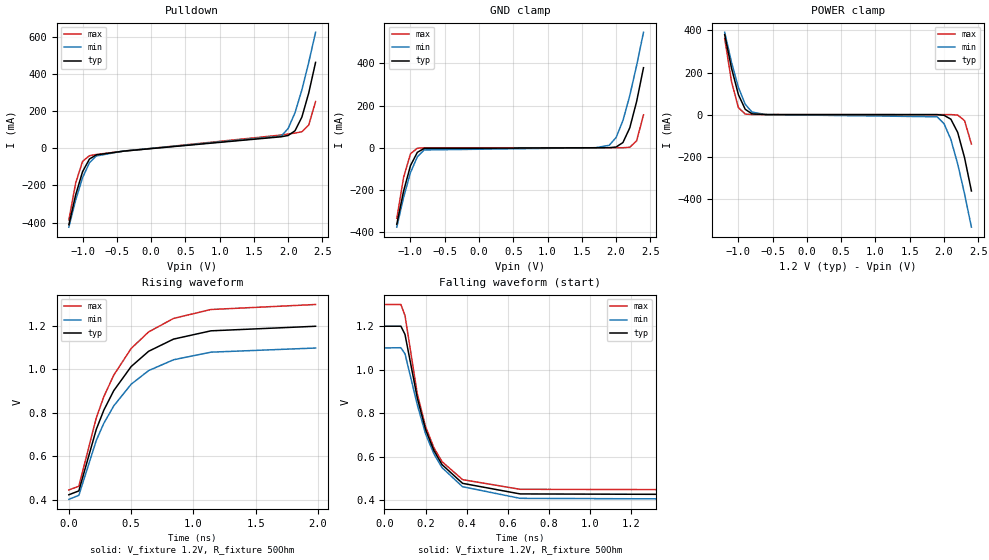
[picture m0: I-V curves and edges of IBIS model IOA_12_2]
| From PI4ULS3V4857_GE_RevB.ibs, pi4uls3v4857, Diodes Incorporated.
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[Model]  IOA_12_2
Model_type  Open_sink
Vmeas=0.8
Vref=1.2
Rref=50
|Variable   typ   min   max
C_comp   4.38p   4.35p   4.41p
|Variable   typ   min   max
[Voltage Range]   1.2   1.1   1.3
[Temperature Range]   40   85   -40
[Pulldown Reference]   0   0   0
[Power Clamp Reference]   1.2   1.1   1.3
[GND Clamp Reference]   0   0   0
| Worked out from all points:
|   slope of the pulldown table from 0 to 0.18 V, typ, clamps not added: 26.9 ohm
|   GND clamp passes 1 mA (typ) near -0.72 V on its own axis
|   POWER clamp passes 1 mA (typ) near -0.72 V on its own axis
|   falling waveform, V_fixture 1.2V, R_fixture 50Ohm: 20-80 % time 143ps typ, 154ps min, 133ps max; typ from 1.2 V to 0.424 V
|   rising waveform, V_fixture 1.2V, R_fixture 50Ohm: 20-80 % time 408ps typ, 410ps min, 406ps max; typ from 0.424 V to 1.2 V
[GND Clamp]
-1.2V     -363mA     -377mA     -335mA
-1.1V     -205mA     -235mA     -140mA
-1V       -84.8mA    -118mA     -28.6mA
-900mV    -21.7mA    -42.8mA    -2.29mA
-800mV    -3.31mA    -10.4mA    -51.5uA
1.7V      183nA      121uA      6.42pA
1.9V      214uA      11.7mA     2.28nA
2V        3.47mA     48.5mA     315nA
2.1V      24.8mA     129mA      39.3uA
2.2V      94.6mA     248mA      2.33mA
2.3V      220mA      391mA      33mA
2.4V      380mA      548mA      156mA
[POWER Clamp]
-1.2V     380mA      391mA      362mA
-1.1V     220mA      248mA      156mA
-1V       94.7mA     129mA      33.1mA
-900mV    24.9mA     48.6mA     2.36mA
-800mV    3.5mA      11.7mA     65.4uA
-600mV    27uA       142uA      19.6uA
1.9V      -320uA     -10.4mA    -62.1uA
2V        -3.38mA    -42.8mA    -65.8uA
2.1V      -21.8mA    -118mA     -120uA
2.2V      -84.9mA    -235mA     -2.36mA
2.3V      -205mA     -377mA     -28.7mA
2.4V      -363mA     -535mA     -140mA
[Pulldown]
| Voltage   I(typ)   I(min)  I(max)
-1.2V     -412mA     -425mA     -386mA
-1.1V     -250mA     -278mA     -186mA
-1V       -126mA     -158mA     -70.7mA
-900mV    -58.2mA    -78mA      -39.8mA
-800mV    -35.5mA    -41.4mA    -33.1mA
-400mV    -15.2mA    -14.6mA    -15.6mA
1.9V      62.2mA     65.8mA     71.5mA
2V        69.2mA     107mA      76.8mA
2.1V      94.5mA     192mA      82mA
2.2V      168mA      315mA      89.2mA
2.3V      298mA      463mA      125mA
2.4V      463mA      625mA      252mA
[Falling Waveform]
V_fixture = 1.2V
V_fixture_min = 1.1V
V_fixture_max = 1.3V
R_fixture = 50Ohm
C_fixture = 0F
|   Time   V(typ)   V(min)   V(max)
0s        1.2V       1.1V       1.3V
80ps      1.2V       1.101V     1.3V
100ps     1.162V     1.073V     1.249V
160ps     869mV      837.4mV    887.5mV
200ps     724.4mV    704.4mV    738.1mV
240ps     628.7mV    613.1mV    641.3mV
280ps     562.8mV    549mV      576.3mV
380ps     476.5mV    460.9mV    493.6mV
660ps     427.8mV    407.4mV    449.1mV
1.98ns    424.2mV    402.9mV    446.3mV
[Rising Waveform]
V_fixture = 1.2V
V_fixture_min = 1.1V
V_fixture_max = 1.3V
R_fixture = 50Ohm
C_fixture = 0F
|   Time   V(typ)   V(min)   V(max)
0s        423.9mV    402.8mV    445.9mV
80ps      441.5mV    421.1mV    463mV
220ps     724.2mV    673.4mV    776.8mV
280ps     811.8mV    751.6mV    873.7mV
360ps     901.9mV    831.9mV    973.1mV
500ps     1.013V     931.8mV    1.096V
640ps     1.083V     994.3mV    1.172V
840ps     1.139V     1.044V     1.234V
1.14ns    1.177V     1.079V     1.275V
1.98ns    1.198V     1.098V     1.298V
[Ramp]
|   typ   min   max
dV/dt_r   0.62/2.47E-10   0.56/2.50E-10   0.68/2.46E-10
dV/dt_f   0.63/1.42E-10   0.56/1.52E-10   0.69/1.34E-10
R_load =   50
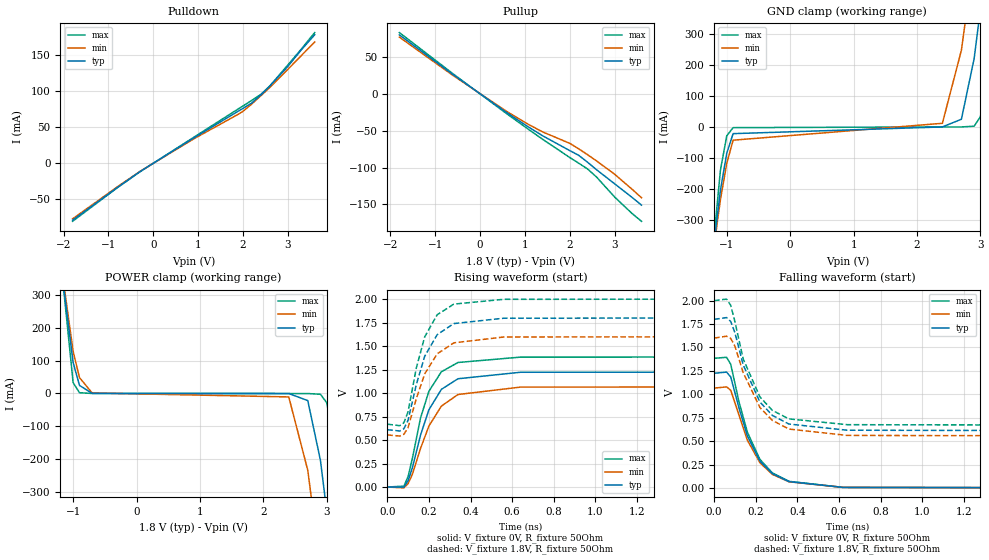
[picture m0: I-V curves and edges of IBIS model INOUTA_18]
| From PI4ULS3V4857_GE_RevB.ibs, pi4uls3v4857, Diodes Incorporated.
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[Model]  INOUTA_18
Model_type  I/O
Vinl = 0.36V
Vinh = 1.44V
Vmeas=0.9
|Variable   typ   min   max
C_comp   4.26p   4.22p   4.30p
|Variable   typ   min   max
[Voltage Range]   1.8   1.6   2.0
[Temperature Range]   40   85   -40
[Pullup Reference]   1.8   1.6   2.0
[Pulldown Reference]   0   0   0
[Power Clamp Reference]   1.8   1.6   2.0
[GND Clamp Reference]   0   0   0
[Driver Schedule]
|Model_Name   Rise_on_dly   Rise_off_dly   Fall_on_dly   Fall_off_dly
IOA_18_1   0.00ns   4.80ns   NA   NA
IOA_18_2   0.00ns   NA   0.00ns   NA
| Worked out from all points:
|   slope of the pulldown table from 0 to 0.27 V, typ, clamps not added: 25.4 ohm
|   slope of the pullup table from 0 to 0.27 V, typ, clamps not added: 23.2 ohm
|   GND clamp passes 1 mA (typ) near -0.72 V on its own axis
|   POWER clamp passes 1 mA (typ) near -0.72 V on its own axis
|   falling waveform, V_fixture 0V, R_fixture 50Ohm: 20-80 % time 129ps typ, 132ps min, 127ps max; typ from 1.22 V to 0.001 V
|   falling waveform, V_fixture 1.8V, R_fixture 50Ohm: 20-80 % time 134ps typ, 139ps min, 129ps max; typ from 1.8 V to 0.611 V
|   rising waveform, V_fixture 0V, R_fixture 50Ohm: 20-80 % time 113ps typ, 125ps min, 102ps max; typ from 0.001 V to 1.22 V
|   rising waveform, V_fixture 1.8V, R_fixture 50Ohm: 20-80 % time 104ps typ, 112ps min, 97.1ps max; typ from 0.611 V to 1.8 V
[GND Clamp]
-1.8V     -1.56A     -1.42A     -1.93A
-1.3V     -542mA     -535mA     -571mA
-1.1V     -205mA     -235mA     -140mA
-1V       -84.8mA    -118mA     -28.6mA
-900mV    -21.7mA    -42.8mA    -2.29mA
2.4V      6.93uA     11.7mA     8.52pA
2.7V      24.8mA     248mA      315nA
2.9V      220mA      548mA      2.33mA
3V        380mA      713mA      33mA
3.1V      561mA      885mA      156mA
3.3V      951mA      1.24A      608mA
3.6V      1.57A      1.79A      1.43A
[POWER Clamp]
-1.8V     1.57A      1.42A      2.01A
-1.3V     561mA      548mA      608mA
-1V       94.7mA     129mA      33.1mA
-900mV    24.9mA     48.6mA     2.36mA
-700mV    238uA      1.67mA     23.2uA
2.4V      -89.8uA    -10.5mA    -78.4uA
2.7V      -21.8mA    -235mA     -88.7uA
2.9V      -205mA     -535mA     -2.39mA
3V        -363mA     -702mA     -28.7mA
3.1V      -542mA     -876mA     -140mA
3.3V      -932mA     -1.24A     -571mA
3.6V      -1.56A     -1.8A      -1.37A
[Pulldown]
| Voltage   I(typ)   I(min)  I(max)
-1.8V     -79mA      -77.1mA    -80.5mA
-800mV    -33.6mA    -32.7mA    -33.9mA
-300mV    -11.8mA    -11.5mA    -12mA
900mV     34.9mA     33.6mA     35.8mA
1.9V      72.3mA     68mA       75.4mA
2V        75.9mA     71.9mA     79.3mA
2.2V      83.6mA     82.2mA     87.2mA
2.4V      94.7mA     93.5mA     95.3mA
2.6V      107mA      105mA      107mA
3V        134mA      130mA      136mA
3.3V      157mA      149mA      158mA
3.6V      178mA      168mA      181mA
[Pullup]   |Note: Vtable = Vcc - Voutput
| Voltage   I(typ)   I(min)  I(max)
-1.8V     80.4mA     77.4mA     83.6mA
-600mV    26.3mA     25.1mA     27.4mA
600mV     -25.5mA    -23.9mA    -27mA
1.1V      -45.6mA    -42mA      -48.9mA
1.4V      -56.9mA    -51.6mA    -61.7mA
2V        -76.9mA    -67mA      -86.3mA
2.2V      -83.3mA    -74.5mA    -94mA
2.4V      -92.9mA    -82.6mA    -102mA
2.6V      -103mA     -91mA      -113mA
3V        -122mA     -109mA     -140mA
3.4V      -141mA     -130mA     -163mA
3.6V      -151mA     -141mA     -173mA
[Falling Waveform]
V_fixture = 0V
V_fixture_min = 0V
V_fixture_max = 0V
R_fixture = 50Ohm
C_fixture = 0F
|   Time   V(typ)   V(min)   V(max)
0s        1.224V     1.066V     1.384V
60ps      1.237V     1.079V     1.395V
80ps      1.185V     1.043V     1.32V
120ps     852.5mV    775.8mV    917mV
160ps     555.2mV    509.5mV    595.4mV
220ps     288.2mV    270mV      306mV
280ps     152.2mV    144.8mV    160.9mV
360ps     67.7mV     65.7mV     70.54mV
620ps     5.789mV    5.873mV    5.809mV
1.98ns    1.014mV    924.2uV    1.09mV
[Falling Waveform]
V_fixture = 1.8V
V_fixture_min = 1.6V
V_fixture_max = 2.0V
R_fixture = 50Ohm
C_fixture = 0F
|   Time   V(typ)   V(min)   V(max)
0s        1.8V       1.6V       2V
60ps      1.819V     1.62V      2.016V
80ps      1.777V     1.596V     1.95V
100ps     1.659V     1.515V     1.777V
140ps     1.313V     1.231V     1.377V
220ps     918.4mV    859.7mV    972.9mV
280ps     774.7mV    720.8mV    828.3mV
360ps     682.2mV    628.6mV    737.2mV
640ps     616.3mV    560.8mV    675.5mV
1.98ns    611mV      555.4mV    669.9mV
[Rising Waveform]
V_fixture = 0V
V_fixture_min = 0V
V_fixture_max = 0V
R_fixture = 50Ohm
C_fixture = 0F
|   Time   V(typ)   V(min)   V(max)
0s        1.014mV    924.1uV    1.09mV
80ps      -483.6uV   -7.821mV   10.41mV
100ps     67.65mV    36.61mV    111.6mV
120ps     201.2mV    132.3mV    299.9mV
160ps     555.1mV    412.4mV    735.9mV
200ps     822.2mV    649.5mV    1.019V
260ps     1.04V      862mV      1.227V
340ps     1.153V     985.3mV    1.326V
640ps     1.222V     1.064V     1.383V
1.98ns    1.224V     1.066V     1.384V
[Rising Waveform]
V_fixture = 1.8V
V_fixture_min = 1.6V
V_fixture_max = 2.0V
R_fixture = 50Ohm
C_fixture = 0F
|   Time   V(typ)   V(min)   V(max)
0s        611mV      555.4mV    669.9mV
60ps      597mV      543.2mV    653.7mV
80ps      620.9mV    562.3mV    685.2mV
100ps     711.7mV    633.5mV    802.4mV
140ps     1.094V     944.3mV    1.27V
180ps     1.393V     1.205V     1.599V
240ps     1.622V     1.418V     1.834V
320ps     1.74V      1.535V     1.947V
560ps     1.797V     1.597V     1.998V
1.98ns    1.8V       1.6V       2V
[Ramp]
|   typ   min   max
dV/dt_r   0.99/0.74E-10   0.86/0.82E-10   1.12/0.66E-10
dV/dt_f   0.99/1.27E-10   0.87/1.31E-10   1.12/1.26E-10
R_load =   50.0000
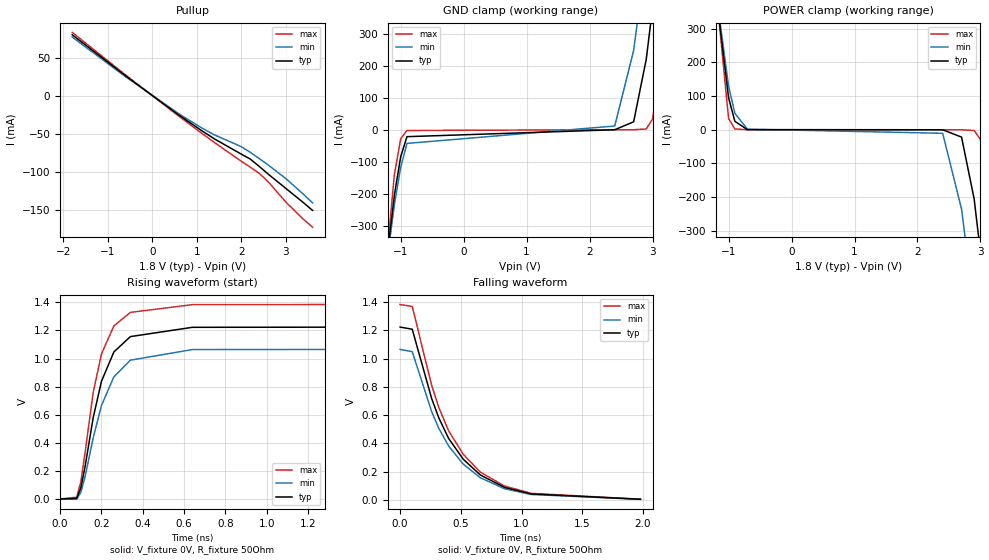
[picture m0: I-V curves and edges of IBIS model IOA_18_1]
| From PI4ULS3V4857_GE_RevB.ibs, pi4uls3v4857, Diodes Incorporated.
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[Model]  IOA_18_1
Model_type  Open_source
Vmeas=0.6
Vref=0
Rref=50
|Variable   typ   min   max
C_comp   4.26p   4.22p   4.30p
|Variable   typ   min   max
[Voltage Range]   1.8   1.6   2.0
[Temperature Range]   40   85   -40
[Pullup Reference]   1.8   1.6   2.0
[Power Clamp Reference]   1.8   1.6   2.0
[GND Clamp Reference]   0   0   0
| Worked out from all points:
|   slope of the pullup table from 0 to 0.27 V, typ, clamps not added: 23.2 ohm
|   GND clamp passes 1 mA (typ) near -0.72 V on its own axis
|   POWER clamp passes 1 mA (typ) near -0.72 V on its own axis
|   falling waveform, V_fixture 0V, R_fixture 50Ohm: 20-80 % time 390ps typ, 395ps min, 387ps max; typ from 1.22 V to 0.005 V
|   rising waveform, V_fixture 0V, R_fixture 50Ohm: 20-80 % time 113ps typ, 125ps min, 102ps max; typ from 0.003 V to 1.22 V
[GND Clamp]
-1.8V     -1.56A     -1.42A     -1.93A
-1.3V     -542mA     -535mA     -571mA
-1.1V     -205mA     -235mA     -140mA
-1V       -84.8mA    -118mA     -28.6mA
-900mV    -21.7mA    -42.8mA    -2.29mA
2.4V      6.93uA     11.7mA     8.52pA
2.7V      24.8mA     248mA      315nA
2.9V      220mA      548mA      2.33mA
3V        380mA      713mA      33mA
3.1V      561mA      885mA      156mA
3.3V      951mA      1.24A      608mA
3.6V      1.57A      1.79A      1.43A
[POWER Clamp]
-1.8V     1.57A      1.42A      2.01A
-1.3V     561mA      548mA      608mA
-1V       94.7mA     129mA      33.1mA
-900mV    24.9mA     48.6mA     2.36mA
-700mV    238uA      1.67mA     23.2uA
2.4V      -89.8uA    -10.5mA    -78.4uA
2.7V      -21.8mA    -235mA     -88.7uA
2.9V      -205mA     -535mA     -2.39mA
3V        -363mA     -702mA     -28.7mA
3.1V      -542mA     -876mA     -140mA
3.3V      -932mA     -1.24A     -571mA
3.6V      -1.56A     -1.8A      -1.37A
[Pullup]   |Note: Vtable = Vcc - Voutput
| Voltage   I(typ)   I(min)  I(max)
-1.8V     80.4mA     77.4mA     83.6mA
-600mV    26.3mA     25.1mA     27.4mA
600mV     -25.5mA    -23.9mA    -27mA
1.1V      -45.6mA    -42mA      -48.9mA
1.4V      -56.9mA    -51.6mA    -61.7mA
2V        -76.9mA    -67mA      -86.3mA
2.2V      -83.3mA    -74.5mA    -94mA
2.4V      -92.9mA    -82.6mA    -102mA
2.6V      -103mA     -91mA      -113mA
3V        -122mA     -109mA     -140mA
3.4V      -141mA     -130mA     -163mA
3.6V      -151mA     -141mA     -173mA
[Falling Waveform]
V_fixture = 0V
V_fixture_min = 0V
V_fixture_max = 0V
R_fixture = 50Ohm
C_fixture = 0F
|   Time   V(typ)   V(min)   V(max)
0s        1.224V     1.066V     1.384V
100ps     1.209V     1.05V      1.37V
260ps     718mV      625.4mV    811.5mV
320ps     578.8mV    505.1mV    652.6mV
400ps     435mV      381.4mV    488.9mV
520ps     288.5mV    253.8mV    323.4mV
660ps     177.5mV    157.5mV    197.8mV
860ps     88.74mV    79.47mV    98.33mV
1.08ns    42.37mV    38.44mV    46.59mV
1.98ns    4.714mV    4.28mV     5.102mV
[Rising Waveform]
V_fixture = 0V
V_fixture_min = 0V
V_fixture_max = 0V
R_fixture = 50Ohm
C_fixture = 0F
|   Time   V(typ)   V(min)   V(max)
0s        3.004mV    2.684mV    3.261mV
80ps      7.001mV    493.1uV    15.39mV
100ps     81.21mV    50.42mV    123.4mV
120ps     227.2mV    156.6mV    325.4mV
160ps     581.3mV    438.1mV    759.7mV
200ps     838.8mV    666.9mV    1.033V
260ps     1.047V     870.6mV    1.232V
340ps     1.156V     988.7mV    1.328V
640ps     1.222V     1.064V     1.383V
1.98ns    1.224V     1.066V     1.384V
[Ramp]
|   typ   min   max
dV/dt_r   0.99/0.74E-10   0.86/0.82E-10   1.12/0.65E-10
dV/dt_f   0.98/3.91E-10   0.86/3.96E-10   1.11/3.87E-10
R_load =   50.0000
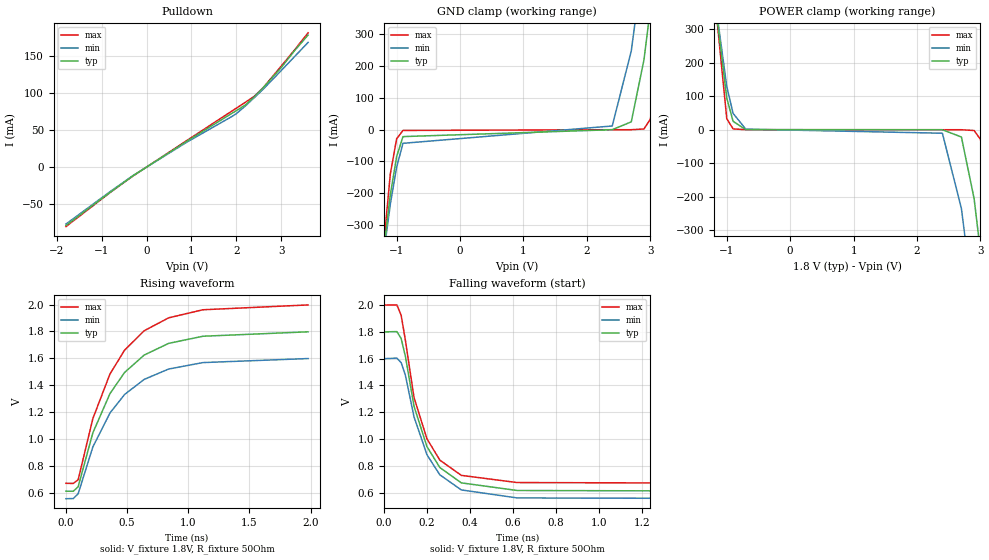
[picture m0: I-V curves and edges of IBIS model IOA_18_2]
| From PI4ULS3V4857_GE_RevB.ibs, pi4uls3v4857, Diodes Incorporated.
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[Model]  IOA_18_2
Model_type  Open_sink
Vmeas=1.0
Vref=1.8
Rref=50
|Variable   typ   min   max
C_comp   4.26p   4.22p   4.30p
|Variable   typ   min   max
[Voltage Range]   1.8   1.6   2.0
[Temperature Range]   40   85   -40
[Pullup Reference]   1.8   1.6   2.0
[Pulldown Reference]   0   0   0
[Power Clamp Reference]   1.8   1.6   2.0
[GND Clamp Reference]   0   0   0
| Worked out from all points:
|   slope of the pulldown table from 0 to 0.27 V, typ, clamps not added: 25.4 ohm
|   GND clamp passes 1 mA (typ) near -0.72 V on its own axis
|   POWER clamp passes 1 mA (typ) near -0.72 V on its own axis
|   falling waveform, V_fixture 1.8V, R_fixture 50Ohm: 20-80 % time 127ps typ, 134ps min, 121ps max; typ from 1.8 V to 0.611 V
|   rising waveform, V_fixture 1.8V, R_fixture 50Ohm: 20-80 % time 392ps typ, 398ps min, 389ps max; typ from 0.611 V to 1.8 V
[GND Clamp]
-1.8V     -1.56A     -1.42A     -1.93A
-1.3V     -542mA     -535mA     -571mA
-1.1V     -205mA     -235mA     -140mA
-1V       -84.8mA    -118mA     -28.6mA
-900mV    -21.7mA    -42.8mA    -2.29mA
2.4V      6.93uA     11.7mA     8.52pA
2.7V      24.8mA     248mA      315nA
2.9V      220mA      548mA      2.33mA
3V        380mA      713mA      33mA
3.1V      561mA      885mA      156mA
3.3V      951mA      1.24A      608mA
3.6V      1.57A      1.79A      1.43A
[POWER Clamp]
-1.8V     1.57A      1.42A      2.01A
-1.3V     561mA      548mA      608mA
-1V       94.7mA     129mA      33.1mA
-900mV    24.9mA     48.6mA     2.36mA
-700mV    238uA      1.67mA     23.2uA
2.4V      -89.8uA    -10.5mA    -78.4uA
2.7V      -21.8mA    -235mA     -88.7uA
2.9V      -205mA     -535mA     -2.39mA
3V        -363mA     -702mA     -28.7mA
3.1V      -542mA     -876mA     -140mA
3.3V      -932mA     -1.24A     -571mA
3.6V      -1.56A     -1.8A      -1.37A
[Pulldown]
| Voltage   I(typ)   I(min)  I(max)
-1.8V     -79mA      -77.1mA    -80.5mA
-800mV    -33.6mA    -32.7mA    -33.9mA
-300mV    -11.8mA    -11.5mA    -12mA
900mV     34.9mA     33.6mA     35.8mA
1.9V      72.3mA     68mA       75.4mA
2V        75.9mA     71.9mA     79.3mA
2.2V      83.6mA     82.2mA     87.2mA
2.4V      94.7mA     93.5mA     95.3mA
2.6V      107mA      105mA      107mA
3V        134mA      130mA      136mA
3.3V      157mA      149mA      158mA
3.6V      178mA      168mA      181mA
[Falling Waveform]
V_fixture = 1.8V
V_fixture_min = 1.6V
V_fixture_max = 2.0V
R_fixture = 50Ohm
C_fixture = 0F
|   Time   V(typ)   V(min)   V(max)
0s        1.8V       1.6V       2V
60ps      1.802V     1.604V     2.001V
80ps      1.751V     1.571V     1.925V
100ps     1.616V     1.475V     1.735V
140ps     1.245V     1.166V     1.31V
200ps     944.6mV    883.9mV    1.003V
260ps     788.3mV    733.8mV    843.5mV
360ps     673.6mV    620.9mV    729.5mV
620ps     616.6mV    561.1mV    675.8mV
1.98ns    611mV      555.4mV    669.9mV
[Rising Waveform]
V_fixture = 1.8V
V_fixture_min = 1.6V
V_fixture_max = 2.0V
R_fixture = 50Ohm
C_fixture = 0F
|   Time   V(typ)   V(min)   V(max)
0s        611mV      555.4mV    669.9mV
60ps      610.8mV    556.2mV    668.9mV
100ps     644mV      592.2mV    696.4mV
220ps     1.045V     940mV      1.151V
360ps     1.337V     1.193V     1.483V
480ps     1.495V     1.331V     1.661V
640ps     1.624V     1.443V     1.805V
840ps     1.711V     1.52V      1.901V
1.12ns    1.764V     1.568V     1.961V
1.98ns    1.797V     1.598V     1.997V
[Ramp]
|   typ   min   max
dV/dt_r   0.95/2.38E-10   0.84/2.41E-10   1.06/2.35E-10
dV/dt_f   0.96/1.29E-10   0.84/1.34E-10   1.07/1.24E-10
R_load =   50
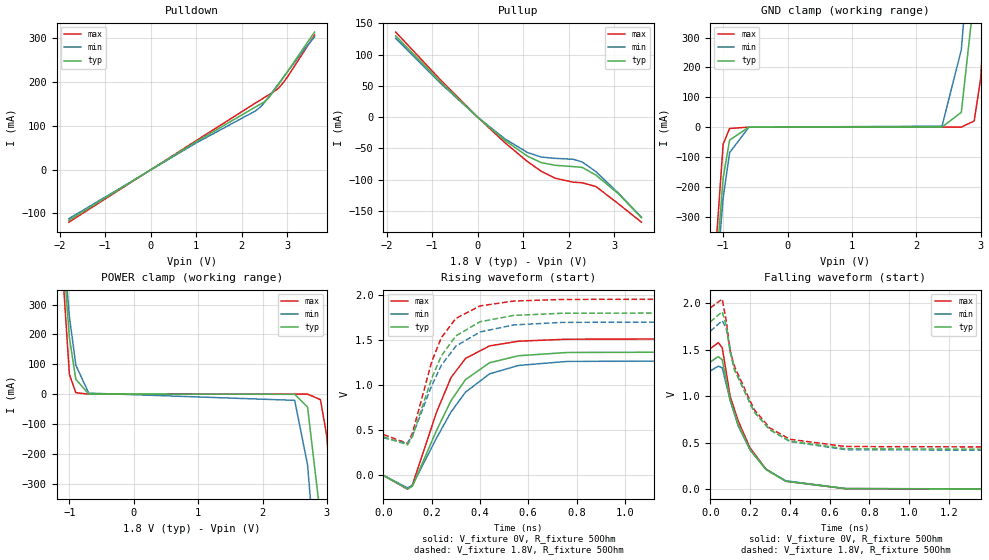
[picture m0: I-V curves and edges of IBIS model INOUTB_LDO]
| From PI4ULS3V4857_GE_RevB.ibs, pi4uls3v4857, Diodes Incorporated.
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[Model]  INOUTB_LDO
Model_type  I/O
Vinl = 0.36V
Vinh = 1.44V
Vmeas=0.9
|Variable   typ   min   max
C_comp   6.81p   6.40p   6.97p
|Variable   typ   min   max
[Voltage Range]   1.8   1.7   1.95
[Temperature Range]   40   85   -40
[Pullup Reference]   1.8   1.7   1.95
[Pulldown Reference]   0   0   0
[Power Clamp Reference]   1.8   1.7   1.95
[GND Clamp Reference]   0   0   0
[Driver Schedule]
|Model_Name   Rise_on_dly   Rise_off_dly   Fall_on_dly   Fall_off_dly
IOB_LDO_1   0.00ns   4.80ns   NA   NA
IOB_LDO_2   0.00ns   NA   0.00ns   NA
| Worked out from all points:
|   slope of the pulldown table from 0 to 0.27 V, typ, clamps not added: 15.5 ohm
|   slope of the pullup table from 0 to 0.27 V, typ, clamps not added: 15.5 ohm
|   GND clamp passes 1 mA (typ) near -0.71 V on its own axis
|   POWER clamp passes 1 mA (typ) near -0.71 V on its own axis
|   falling waveform, V_fixture 0V, R_fixture 50Ohm: 20-80 % time 162ps typ, 166ps min, 160ps max; typ from 1.37 V to 0 V
|   falling waveform, V_fixture 1.8V, R_fixture 50Ohm: 20-80 % time 173ps typ, 177ps min, 167ps max; typ from 1.8 V to 0.426 V
|   rising waveform, V_fixture 0V, R_fixture 50Ohm: 20-80 % time 168ps typ, 188ps min, 139ps max; typ from 0 V to 1.37 V
|   rising waveform, V_fixture 1.8V, R_fixture 50Ohm: 20-80 % time 140ps typ, 152ps min, 121ps max; typ from 0.426 V to 1.8 V
[GND Clamp]
-1.8V     -3.11A     -2.84A     -3.86A
-1.2V     -725mA     -754mA     -669mA
-1V       -170mA     -237mA     -57.3mA
-900mV    -43.4mA    -85.5mA    -4.58mA
-600mV    -19.2uA    -301uA     -6.81nA
2.4V      13.9uA     3.3mA      19.8pA
2.7V      49.7mA     259mA      7.25uA
2.9V      440mA      782mA      20.6mA
3V        761mA      1.1A       162mA
3.1V      1.12A      1.43A      503mA
3.2V      1.5A       1.77A      963mA
3.6V      3.15A      3.21A      3.16A
[POWER Clamp]
-1.8V     3.15A      2.84A      4.03A
-1.2V     761mA      782mA      724mA
-1V       189mA      259mA      66.1mA
-900mV    49.7mA     97.1mA     4.69mA
-700mV    452uA      3.32mA     23.4uA
2.5V      -596uA     -20.8mA    -81.4uA
2.7V      -43.5mA    -237mA     -98.1uA
2.9V      -410mA     -754mA     -18.4mA
3V        -725mA     -1.07A     -142mA
3.1V      -1.08A     -1.4A      -460mA
3.2V      -1.47A     -1.75A     -899mA
3.6V      -3.11A     -3.22A     -3.02A
[Pulldown]
| Voltage   I(typ)   I(min)  I(max)
-1.8V     -116mA     -112mA     -120mA
1V        63.9mA     61mA       66.2mA
2.3V      143mA      134mA      152mA
2.4V      149mA      142mA      158mA
2.5V      155mA      153mA      165mA
2.6V      165mA      167mA      171mA
2.8V      193mA      195mA      185mA
2.9V      208mA      209mA      197mA
3V        223mA      223mA      211mA
3.4V      284mA      278mA      275mA
3.6V      314mA      303mA      307mA
[Pullup]   |Note: Vtable = Vcc - Voutput
| Voltage   I(typ)   I(min)  I(max)
-1.8V     130mA      126mA      136mA
-800mV    55.3mA     53.1mA     58.4mA
0V        15.2pA     41pA       15.6pA
600mV     -37.3mA    -34.8mA    -40.9mA
1.1V      -62.6mA    -56.8mA    -71.3mA
1.4V      -72.8mA    -63.8mA    -86.6mA
1.7V      -77mA      -65.9mA    -97.7mA
2.1V      -79.1mA    -67.4mA    -104mA
2.3V      -80.4mA    -71.7mA    -105mA
2.6V      -92.8mA    -87.2mA    -111mA
3.1V      -123mA     -122mA     -139mA
3.6V      -161mA     -160mA     -168mA
[Falling Waveform]
V_fixture = 0V
V_fixture_min = 0V
V_fixture_max = 0V
R_fixture = 50Ohm
C_fixture = 0F
|   Time   V(typ)   V(min)   V(max)
0s        1.368V     1.273V     1.512V
40ps      1.427V     1.324V     1.577V
60ps      1.393V     1.307V     1.524V
100ps     957.6mV    955mV      999.2mV
140ps     700.1mV    682.9mV    736.7mV
200ps     425.4mV    421.9mV    443.5mV
280ps     211mV      214.5mV    216.8mV
380ps     84.95mV    90.05mV    85.42mV
680ps     5.872mV    6.478mV    5.434mV
1.98ns    -762.7nV   5.088uV    -2.572uV
[Falling Waveform]
V_fixture = 1.8V
V_fixture_min = 1.7V
V_fixture_max = 1.95V
R_fixture = 50Ohm
C_fixture = 0F
|   Time   V(typ)   V(min)   V(max)
0s        1.8V       1.7V       1.95V
60ps      1.91V      1.813V     2.046V
80ps      1.762V     1.731V     1.815V
100ps     1.477V     1.509V     1.487V
120ps     1.295V     1.295V     1.33V
220ps     836.1mV    833.6mV    859mV
300ps     638.6mV    639.5mV    658.2mV
400ps     517.1mV    513.7mV    537.2mV
680ps     434.6mV    424.7mV    458.8mV
1.98ns    426.2mV    415.1mV    451.4mV
[Rising Waveform]
V_fixture = 0V
V_fixture_min = 0V
V_fixture_max = 0V
R_fixture = 50Ohm
C_fixture = 0F
|   Time   V(typ)   V(min)   V(max)
0s        122.5uV    141.4uV    94.05uV
100ps     -150.9mV   -137.8mV   -152.7mV
120ps     -121.2mV   -110.9mV   -106.7mV
220ps     496.1mV    413.1mV    697.7mV
280ps     825.5mV    700.2mV    1.081V
340ps     1.059V     920.1mV    1.293V
440ps     1.246V     1.123V     1.432V
560ps     1.323V     1.216V     1.484V
760ps     1.359V     1.26V      1.506V
1.98ns    1.368V     1.273V     1.512V
[Rising Waveform]
V_fixture = 1.8V
V_fixture_min = 1.7V
V_fixture_max = 1.95V
R_fixture = 50Ohm
C_fixture = 0F
|   Time   V(typ)   V(min)   V(max)
0s        426.3mV    415.2mV    451.5mV
100ps     337.8mV    352.9mV    353.3mV
120ps     428mV      435.1mV    464.7mV
200ps     1.071V     991.5mV    1.256V
240ps     1.322V     1.217V     1.523V
300ps     1.542V     1.429V     1.736V
400ps     1.699V     1.586V     1.874V
540ps     1.769V     1.664V     1.928V
740ps     1.793V     1.692V     1.946V
1.98ns    1.8V       1.7V       1.95V
[Ramp]
|   typ   min   max
dV/dt_r   1.14/1.65E-10   1.06/1.69E-10   1.27/1.64E-10
dV/dt_f   1.27/1.22E-10   1.13/1.36E-10   1.33/1.00E-10
R_load =   50.0000
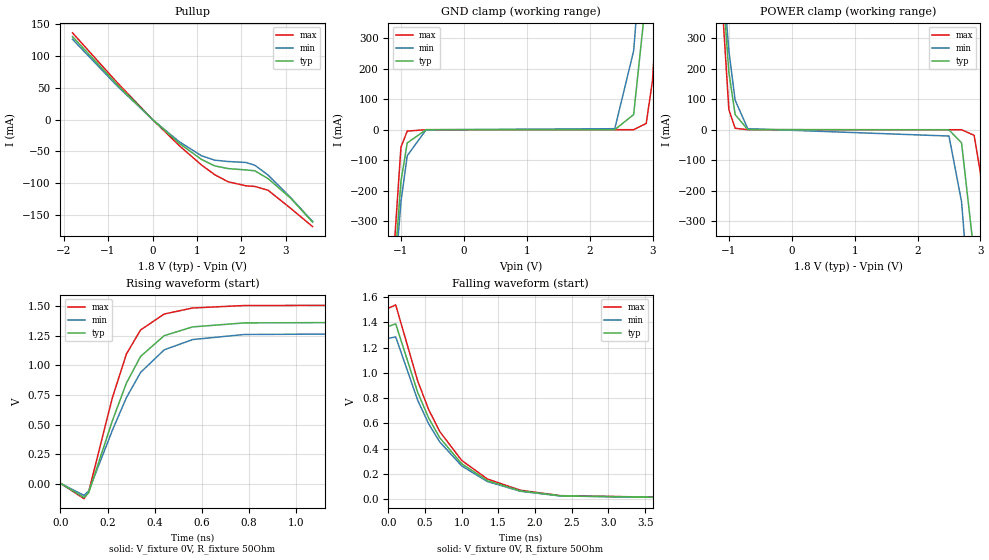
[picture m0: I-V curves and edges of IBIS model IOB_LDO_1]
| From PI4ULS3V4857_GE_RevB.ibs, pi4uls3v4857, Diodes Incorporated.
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[Model]  IOB_LDO_1
Model_type  Open_source
Vmeas=0.6
Vref=0
Rref=50
|Variable   typ   min   max
C_comp   6.81p   6.40p   6.97p
|Variable   typ   min   max
[Voltage Range]   1.8   1.7   1.95
[Temperature Range]   40   85   -40
[Pullup Reference]   1.8   1.7   1.95
[Power Clamp Reference]   1.8   1.7   1.95
[GND Clamp Reference]   0   0   0
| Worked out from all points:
|   slope of the pullup table from 0 to 0.27 V, typ, clamps not added: 15.5 ohm
|   GND clamp passes 1 mA (typ) near -0.71 V on its own axis
|   POWER clamp passes 1 mA (typ) near -0.71 V on its own axis
|   falling waveform, V_fixture 0V, R_fixture 50Ohm: 20-80 % time 749ps typ, 758ps min, 742ps max; typ from 1.37 V to 0.003 V
|   rising waveform, V_fixture 0V, R_fixture 50Ohm: 20-80 % time 168ps typ, 188ps min, 140ps max; typ from 0.003 V to 1.37 V
[GND Clamp]
-1.8V     -3.11A     -2.84A     -3.86A
-1.2V     -725mA     -754mA     -669mA
-1V       -170mA     -237mA     -57.3mA
-900mV    -43.4mA    -85.5mA    -4.58mA
-600mV    -19.2uA    -301uA     -6.81nA
2.4V      13.9uA     3.3mA      19.8pA
2.7V      49.7mA     259mA      7.25uA
2.9V      440mA      782mA      20.6mA
3V        761mA      1.1A       162mA
3.1V      1.12A      1.43A      503mA
3.2V      1.5A       1.77A      963mA
3.6V      3.15A      3.21A      3.16A
[POWER Clamp]
-1.8V     3.15A      2.84A      4.03A
-1.2V     761mA      782mA      724mA
-1V       189mA      259mA      66.1mA
-900mV    49.7mA     97.1mA     4.69mA
-700mV    452uA      3.32mA     23.4uA
2.5V      -596uA     -20.8mA    -81.4uA
2.7V      -43.5mA    -237mA     -98.1uA
2.9V      -410mA     -754mA     -18.4mA
3V        -725mA     -1.07A     -142mA
3.1V      -1.08A     -1.4A      -460mA
3.2V      -1.47A     -1.75A     -899mA
3.6V      -3.11A     -3.22A     -3.02A
[Pullup]   |Note: Vtable = Vcc - Voutput
| Voltage   I(typ)   I(min)  I(max)
-1.8V     130mA      126mA      136mA
-800mV    55.3mA     53.1mA     58.4mA
0V        15.2pA     41pA       15.6pA
600mV     -37.3mA    -34.8mA    -40.9mA
1.1V      -62.6mA    -56.8mA    -71.3mA
1.4V      -72.8mA    -63.8mA    -86.6mA
1.7V      -77mA      -65.9mA    -97.7mA
2.1V      -79.1mA    -67.4mA    -104mA
2.3V      -80.4mA    -71.7mA    -105mA
2.6V      -92.8mA    -87.2mA    -111mA
3.1V      -123mA     -122mA     -139mA
3.6V      -161mA     -160mA     -168mA
[Falling Waveform]
V_fixture = 0V
V_fixture_min = 0V
V_fixture_max = 0V
R_fixture = 50Ohm
C_fixture = 0F
|   Time   V(typ)   V(min)   V(max)
0s        1.368V     1.273V     1.512V
100ps     1.388V     1.285V     1.538V
400ps     845mV      782.5mV    935.2mV
550ps     641.2mV    595.6mV    707.7mV
700ps     486.3mV    452.9mV    535.3mV
1ns       279.3mV    262.5mV    305.8mV
1.35ns    146.2mV    138.7mV    159.2mV
1.8ns     64.77mV    61.77mV    69.9mV
2.35ns    25.37mV    24.49mV    27.15mV
4.95ns    3.267mV    3.134mV    3.42mV
[Rising Waveform]
V_fixture = 0V
V_fixture_min = 0V
V_fixture_max = 0V
R_fixture = 50Ohm
C_fixture = 0F
|   Time   V(typ)   V(min)   V(max)
0s        2.995mV    2.842mV    3.17mV
100ps     -117.2mV   -99.13mV   -127.1mV
120ps     -74.76mV   -61.46mV   -66.85mV
220ps     531.5mV    450.9mV    726.8mV
280ps     852.1mV    728.9mV    1.098V
340ps     1.077V     941.6mV    1.301V
440ps     1.252V     1.132V     1.435V
560ps     1.326V     1.219V     1.486V
780ps     1.36V      1.262V     1.507V
1.98ns    1.368V     1.273V     1.512V
[Ramp]
|   typ   min   max
dV/dt_r   1.19/1.21E-10   1.10/1.34E-10   1.31/1.00E-10
dV/dt_f   1.12/7.46E-10   1.04/7.53E-10   1.24/7.40E-10
R_load =   50.0000
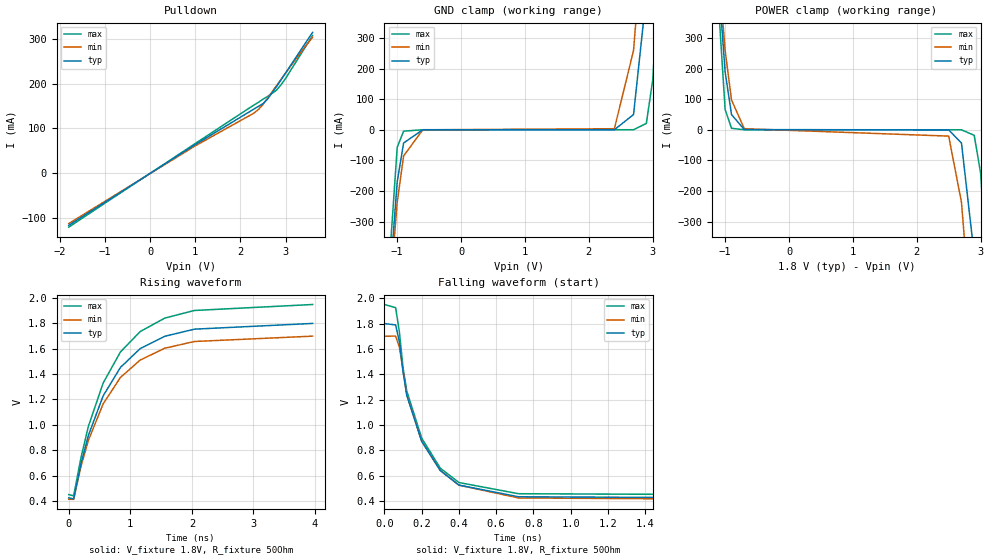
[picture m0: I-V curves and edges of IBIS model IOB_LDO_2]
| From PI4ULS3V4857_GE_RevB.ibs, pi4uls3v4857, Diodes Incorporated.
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[Model]  IOB_LDO_2
Model_type  Open_sink
Vmeas=0.9
Vref=1.2
Rref=50
|Variable   typ   min   max
C_comp   6.81p   6.40p   6.97p
|Variable   typ   min   max
[Voltage Range]   1.8   1.7   1.95
[Temperature Range]   40   85   -40
[Pullup Reference]   1.8   1.7   1.95
[Pulldown Reference]   0   0   0
[Power Clamp Reference]   1.8   1.7   1.95
[GND Clamp Reference]   0   0   0
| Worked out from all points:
|   slope of the pulldown table from 0 to 0.27 V, typ, clamps not added: 15.5 ohm
|   GND clamp passes 1 mA (typ) near -0.71 V on its own axis
|   POWER clamp passes 1 mA (typ) near -0.71 V on its own axis
|   falling waveform, V_fixture 1.8V, R_fixture 50Ohm: 20-80 % time 176ps typ, 185ps min, 167ps max; typ from 1.8 V to 0.426 V
|   rising waveform, V_fixture 1.8V, R_fixture 50Ohm: 20-80 % time 772ps typ, 779ps min, 764ps max; typ from 0.426 V to 1.8 V
[GND Clamp]
-1.8V     -3.11A     -2.84A     -3.86A
-1.2V     -725mA     -754mA     -669mA
-1V       -170mA     -237mA     -57.3mA
-900mV    -43.4mA    -85.5mA    -4.58mA
-600mV    -19.2uA    -301uA     -6.81nA
2.4V      13.9uA     3.3mA      19.8pA
2.7V      49.7mA     259mA      7.25uA
2.9V      440mA      782mA      20.6mA
3V        761mA      1.1A       162mA
3.1V      1.12A      1.43A      503mA
3.2V      1.5A       1.77A      963mA
3.6V      3.15A      3.21A      3.16A
[POWER Clamp]
-1.8V     3.15A      2.84A      4.03A
-1.2V     761mA      782mA      724mA
-1V       189mA      259mA      66.1mA
-900mV    49.7mA     97.1mA     4.69mA
-700mV    452uA      3.32mA     23.4uA
2.5V      -596uA     -20.8mA    -81.4uA
2.7V      -43.5mA    -237mA     -98.1uA
2.9V      -410mA     -754mA     -18.4mA
3V        -725mA     -1.07A     -142mA
3.1V      -1.08A     -1.4A      -460mA
3.2V      -1.47A     -1.75A     -899mA
3.6V      -3.11A     -3.22A     -3.02A
[Pulldown]
| Voltage   I(typ)   I(min)  I(max)
-1.8V     -116mA     -112mA     -120mA
1V        63.9mA     61mA       66.2mA
2.3V      143mA      134mA      152mA
2.4V      149mA      142mA      158mA
2.5V      155mA      153mA      165mA
2.6V      165mA      167mA      171mA
2.8V      193mA      195mA      185mA
2.9V      208mA      209mA      197mA
3V        223mA      223mA      211mA
3.4V      284mA      278mA      275mA
3.6V      314mA      303mA      307mA
[Falling Waveform]
V_fixture = 1.8V
V_fixture_min = 1.7V
V_fixture_max = 1.95V
R_fixture = 50Ohm
C_fixture = 0F
|   Time   V(typ)   V(min)   V(max)
0s        1.8V       1.7V       1.95V
60ps      1.789V     1.701V     1.925V
80ps      1.656V     1.615V     1.736V
100ps     1.419V     1.431V     1.449V
120ps     1.234V     1.239V     1.268V
200ps     872mV      873.2mV    897mV
300ps     641.4mV    643.2mV    660.3mV
400ps     527.2mV    526.6mV    547.5mV
720ps     435.4mV    426mV      459.4mV
1.98ns    426.3mV    415.2mV    451.5mV
[Rising Waveform]
V_fixture = 1.8V
V_fixture_min = 1.7V
V_fixture_max = 1.95V
R_fixture = 50Ohm
C_fixture = 0F
|   Time   V(typ)   V(min)   V(max)
0s        426.3mV    415.2mV    451.5mV
80ps      417.6mV    414.3mV    441.7mV
200ps     695.7mV    675.3mV    744mV
320ps     918.6mV    879.9mV    990mV
560ps     1.229V     1.166V     1.33V
840ps     1.452V     1.373V     1.574V
1.16ns    1.6V       1.51V      1.734V
1.56ns    1.697V     1.603V     1.84V
2.04ns    1.753V     1.656V     1.9V
3.96ns    1.798V     1.698V     1.947V
[Ramp]
|   typ   min   max
dV/dt_r   1.11/4.60E-10   1.03/4.65E-10   1.21/4.56E-10
dV/dt_f   1.11/1.86E-10   1.04/1.95E-10   1.21/1.79E-10
R_load =   50
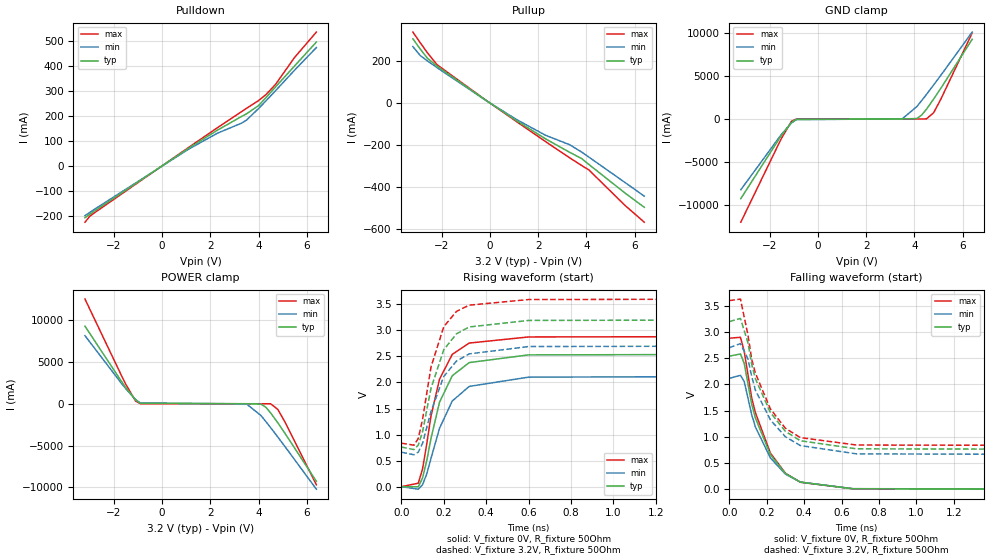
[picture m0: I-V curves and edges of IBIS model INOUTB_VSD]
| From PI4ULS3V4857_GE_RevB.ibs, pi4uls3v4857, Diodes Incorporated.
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[Model]  INOUTB_VSD
Model_type  I/O
Vinl = 0.64V
Vinh = 2.56V
Vmeas=1.6
|Variable   typ   min   max
C_comp   4.65p   4.39p   5.09p
|Variable   typ   min   max
[Voltage Range]   3.2   2.7   3.6
[Temperature Range]   40   85   -40
[Pullup Reference]   3.2   2.7   3.6
[Pulldown Reference]   0   0   0
[Power Clamp Reference]   3.2   2.7   3.6
[GND Clamp Reference]   0   0   0
[Driver Schedule]
|Model_Name   Rise_on_dly   Rise_off_dly   Fall_on_dly   Fall_off_dly
IOB_VSD_1   0.00ns   4.80ns   NA   NA
IOB_VSD_2   0.00ns   NA   0.00ns   NA
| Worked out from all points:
|   slope of the pulldown table from 0 to 0.48 V, typ, clamps not added: 15.6 ohm
|   slope of the pullup table from 0 to 0.48 V, typ, clamps not added: 13 ohm
|   GND clamp passes 1 mA (typ) near -0.71 V on its own axis
|   POWER clamp passes 1 mA (typ) near -0.71 V on its own axis
|   falling waveform, V_fixture 0V, R_fixture 50Ohm: 20-80 % time 148ps typ, 154ps min, 144ps max; typ from 2.54 V to 0 V
|   falling waveform, V_fixture 3.2V, R_fixture 50Ohm: 20-80 % time 157ps typ, 167ps min, 150ps max; typ from 3.2 V to 0.761 V
|   rising waveform, V_fixture 0V, R_fixture 50Ohm: 20-80 % time 104ps typ, 118ps min, 94.5ps max; typ from 0 V to 2.54 V
|   rising waveform, V_fixture 3.2V, R_fixture 50Ohm: 20-80 % time 104ps typ, 114ps min, 93.9ps max; typ from 0.761 V to 3.2 V
[GND Clamp]
-3.2V     -9.26A     -8.23A     -12A
-1.6V     -2.27A     -2.11A     -2.74A
-1.5V     -1.86A     -1.75A     -2.19A
-1.1V     -409mA     -469mA     -279mA
-900mV    -43.4mA    -85.5mA    -4.58mA
3.5V      258pA      23.4mA     20.4pA
4.1V      49.7mA     1.43A      60.1pA
4.3V      440mA      2.12A      630nA
4.5V      1.12A      2.84A      4.66mA
4.8V      2.31A      3.95A      723mA
5.1V      3.57A      5.08A      2.3A
6.4V      9.26A      10.1A      10A
[POWER Clamp]
-3.2V     9.26A      8.13A      12.5A
-1.7V     2.73A      2.48A      3.45A
-1.5V     1.9A       1.77A      2.3A
-1.1V     440mA      496mA      311mA
-900mV    49.7mA     97.1mA     4.69mA
3.5V      -117uA     -20.9mA    -114uA
4.1V      -43.5mA    -1.4A      -134uA
4.3V      -410mA     -2.11A     -141uA
4.5V      -1.08A     -2.84A     -4.73mA
4.8V      -2.27A     -3.97A     -670mA
5.1V      -3.54A     -5.12A     -2.19A
6.4V      -9.26A     -10.2A     -9.67A
[Pulldown]
| Voltage   I(typ)   I(min)  I(max)
-3.2V     -208mA     -200mA     -226mA
-3V       -194mA     -187mA     -202mA
-2.8V     -181mA     -174mA     -188mA
1.1V      70mA       65.9mA     72.8mA
2.3V      142mA      130mA      152mA
3.3V      197mA      170mA      216mA
3.5V      207mA      182mA      229mA
4V        240mA      228mA      260mA
4.3V      271mA      258mA      283mA
4.7V      314mA      299mA      324mA
5.5V      399mA      382mA      433mA
6.4V      494mA      472mA      534mA
[Pullup]   |Note: Vtable = Vcc - Voutput
| Voltage   I(typ)   I(min)  I(max)
-3.2V     306mA      269mA      338mA
-2.9V     258mA      227mA      288mA
-2.6V     214mA      201mA      240mA
-2.2V     176mA      169mA      183mA
-200mV    15.6mA     14.8mA     16.2mA
1.1V      -83.9mA    -78.2mA    -88.1mA
2.3V      -170mA     -153mA     -183mA
3.3V      -234mA     -198mA     -260mA
3.8V      -264mA     -233mA     -297mA
4.1V      -292mA     -257mA     -318mA
5.6V      -428mA     -378mA     -487mA
6.4V      -496mA     -443mA     -567mA
[Falling Waveform]
V_fixture = 0V
V_fixture_min = 0V
V_fixture_max = 0V
R_fixture = 50Ohm
C_fixture = 0F
|   Time   V(typ)   V(min)   V(max)
0s        2.54V      2.116V     2.882V
60ps      2.582V     2.174V     2.9V
80ps      2.403V     2.056V     2.636V
120ps     1.624V     1.423V     1.742V
140ps     1.358V     1.186V     1.46V
220ps     658.1mV    596.5mV    688.7mV
300ps     301mV      287.5mV    305.1mV
380ps     134.5mV    135.4mV    131.9mV
660ps     8.139mV    9.525mV    7.337mV
1.98ns    7.658uV    11.33uV    -1.339uV
[Falling Waveform]
V_fixture = 3.2V
V_fixture_min = 2.7V
V_fixture_max = 3.6V
R_fixture = 50Ohm
C_fixture = 0F
|   Time   V(typ)   V(min)   V(max)
0s        3.2V       2.7V       3.6V
60ps      3.26V      2.78V      3.63V
100ps     2.797V     2.486V     2.945V
120ps     2.386V     2.155V     2.481V
140ps     2.106V     1.89V      2.213V
220ps     1.463V     1.323V     1.531V
300ps     1.104V     1.001V     1.163V
380ps     924.7mV    832.5mV    984.6mV
680ps     770.3mV    674.1mV    842.8mV
1.98ns    760.6mV    662.3mV    834.7mV
[Rising Waveform]
V_fixture = 0V
V_fixture_min = 0V
V_fixture_max = 0V
R_fixture = 50Ohm
C_fixture = 0F
|   Time   V(typ)   V(min)   V(max)
0s        217.9uV    224.7uV    173.8uV
80ps      -2.071mV   -47.56mV   66.64mV
100ps     165.3mV    36.39mV    339.7mV
120ps     501.7mV    247.3mV    824.9mV
140ps     927.5mV    543.3mV    1.356V
180ps     1.619V     1.12V      2.061V
240ps     2.128V     1.643V     2.538V
320ps     2.381V     1.924V     2.756V
600ps     2.529V     2.102V     2.873V
1.98ns    2.54V      2.116V     2.882V
[Rising Waveform]
V_fixture = 3.2V
V_fixture_min = 2.7V
V_fixture_max = 3.6V
R_fixture = 50Ohm
C_fixture = 0F
|   Time   V(typ)   V(min)   V(max)
0s        760.8mV    662.6mV    834.9mV
60ps      711.3mV    612mV      796mV
80ps      799mV      663.2mV    926.5mV
100ps     1.054V     831.7mV    1.288V
140ps     1.887V     1.445V     2.298V
200ps     2.627V     2.115V     3.068V
260ps     2.933V     2.41V      3.363V
320ps     3.065V     2.548V     3.483V
600ps     3.19V      2.689V     3.591V
1.98ns    3.2V       2.7V       3.6V
[Ramp]
|   typ   min   max
dV/dt_r   2.08/0.66E-10   1.75/0.76E-10   2.35/0.60E-10
dV/dt_f   2.09/1.50E-10   1.75/1.57E-10   2.36/1.46E-10
R_load =   50.0000
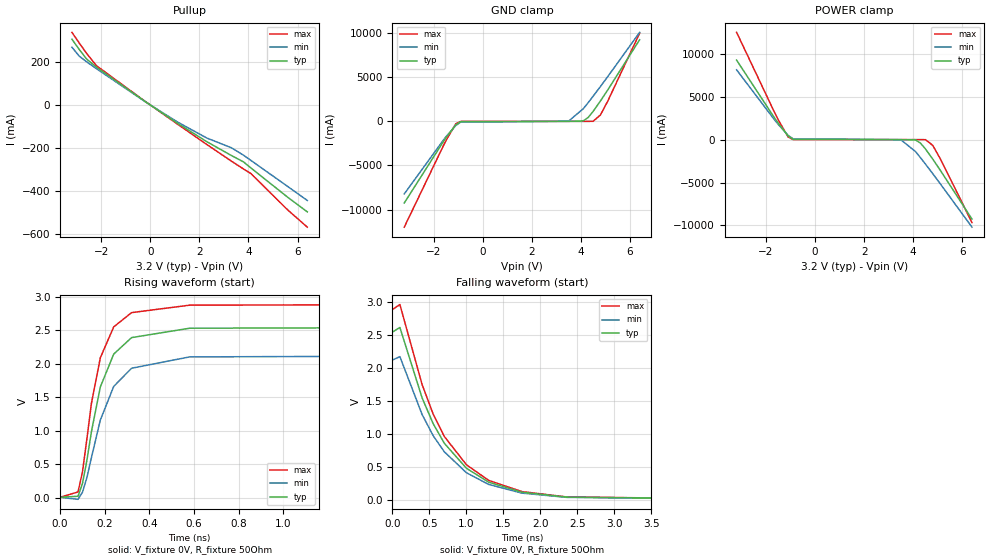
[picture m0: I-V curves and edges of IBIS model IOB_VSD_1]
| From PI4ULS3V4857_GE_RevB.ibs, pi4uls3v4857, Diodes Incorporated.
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[Model]  IOB_VSD_1
Model_type  Open_source
Vmeas=1.0
Vref=0
Rref=50
|Variable   typ   min   max
C_comp   4.65p   4.39p   5.09p
|Variable   typ   min   max
[Voltage Range]   3.2   2.7   3.6
[Temperature Range]   40   85   -40
[Pullup Reference]   3.2   2.7   3.6
[Power Clamp Reference]   3.2   2.7   3.6
[GND Clamp Reference]   0   0   0
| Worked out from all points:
|   slope of the pullup table from 0 to 0.48 V, typ, clamps not added: 13 ohm
|   GND clamp passes 1 mA (typ) near -0.71 V on its own axis
|   POWER clamp passes 1 mA (typ) near -0.71 V on its own axis
|   falling waveform, V_fixture 0V, R_fixture 50Ohm: 20-80 % time 705ps typ, 721ps min, 696ps max; typ from 2.54 V to 0.006 V
|   rising waveform, V_fixture 0V, R_fixture 50Ohm: 20-80 % time 104ps typ, 118ps min, 93.9ps max; typ from 0.005 V to 2.54 V
[GND Clamp]
-3.2V     -9.26A     -8.23A     -12A
-1.6V     -2.27A     -2.11A     -2.74A
-1.5V     -1.86A     -1.75A     -2.19A
-1.1V     -409mA     -469mA     -279mA
-900mV    -43.4mA    -85.5mA    -4.58mA
3.5V      258pA      23.4mA     20.4pA
4.1V      49.7mA     1.43A      60.1pA
4.3V      440mA      2.12A      630nA
4.5V      1.12A      2.84A      4.66mA
4.8V      2.31A      3.95A      723mA
5.1V      3.57A      5.08A      2.3A
6.4V      9.26A      10.1A      10A
[POWER Clamp]
-3.2V     9.26A      8.13A      12.5A
-1.7V     2.73A      2.48A      3.45A
-1.5V     1.9A       1.77A      2.3A
-1.1V     440mA      496mA      311mA
-900mV    49.7mA     97.1mA     4.69mA
3.5V      -117uA     -20.9mA    -114uA
4.1V      -43.5mA    -1.4A      -134uA
4.3V      -410mA     -2.11A     -141uA
4.5V      -1.08A     -2.84A     -4.73mA
4.8V      -2.27A     -3.97A     -670mA
5.1V      -3.54A     -5.12A     -2.19A
6.4V      -9.26A     -10.2A     -9.67A
[Pullup]   |Note: Vtable = Vcc - Voutput
| Voltage   I(typ)   I(min)  I(max)
-3.2V     306mA      269mA      338mA
-2.9V     258mA      227mA      288mA
-2.6V     214mA      201mA      240mA
-2.2V     176mA      169mA      183mA
-200mV    15.6mA     14.8mA     16.2mA
1.1V      -83.9mA    -78.2mA    -88.1mA
2.3V      -170mA     -153mA     -183mA
3.3V      -234mA     -198mA     -260mA
3.8V      -264mA     -233mA     -297mA
4.1V      -292mA     -257mA     -318mA
5.6V      -428mA     -378mA     -487mA
6.4V      -496mA     -443mA     -567mA
[Falling Waveform]
V_fixture = 0V
V_fixture_min = 0V
V_fixture_max = 0V
R_fixture = 50Ohm
C_fixture = 0F
|   Time   V(typ)   V(min)   V(max)
0s        2.54V      2.116V     2.882V
100ps     2.61V      2.168V     2.958V
400ps     1.544V     1.291V     1.746V
550ps     1.151V     969.3mV    1.296V
700ps     855.3mV    726.5mV    958.7mV
1ns       474.8mV    407.6mV    528.4mV
1.3ns     264.9mV    230.8mV    292mV
1.75ns    112.1mV    99.05mV    122.2mV
2.35ns    38.7mV     35.02mV    41.48mV
4.95ns    5.704mV    4.892mV    6.195mV
[Rising Waveform]
V_fixture = 0V
V_fixture_min = 0V
V_fixture_max = 0V
R_fixture = 50Ohm
C_fixture = 0F
|   Time   V(typ)   V(min)   V(max)
0s        5.326mV    4.515mV    5.854mV
80ps      20.26mV    -25.48mV   84.14mV
100ps     210.8mV    80.38mV    383.6mV
120ps     559.6mV    301.8mV    880.6mV
140ps     980.8mV    595.2mV    1.404V
180ps     1.651V     1.158V     2.087V
240ps     2.142V     1.66V      2.548V
320ps     2.388V     1.931V     2.761V
580ps     2.528V     2.1V       2.872V
1.98ns    2.54V      2.116V     2.882V
[Ramp]
|   typ   min   max
dV/dt_r   2.07/0.67E-10   1.73/0.77E-10   2.34/0.60E-10
dV/dt_f   2.09/7.01E-10   1.74/7.18E-10   2.36/6.93E-10
R_load =   50.0000
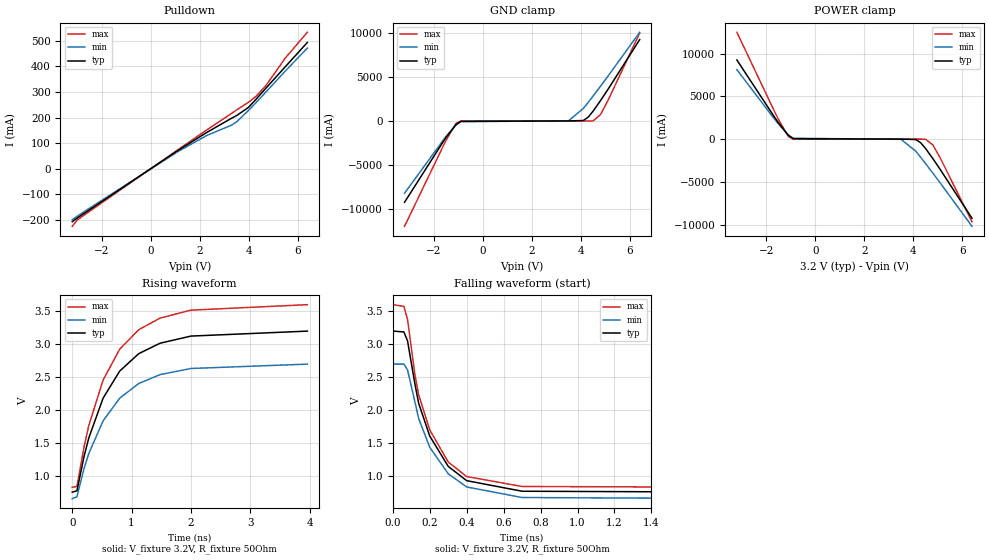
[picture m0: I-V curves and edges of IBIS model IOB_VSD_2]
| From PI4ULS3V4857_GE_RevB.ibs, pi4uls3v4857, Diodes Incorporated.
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[Model]  IOB_VSD_2
Model_type  Open_sink
Vmeas=1.6
Vref=3.2
Rref=50
|Variable   typ   min   max
C_comp   4.65p   4.39p   5.09p
|Variable   typ   min   max
[Voltage Range]   3.2   2.7   3.6
[Temperature Range]   40   85   -40
[Pullup Reference]   3.2   2.7   3.6
[Pulldown Reference]   0   0   0
[Power Clamp Reference]   3.2   2.7   3.6
[GND Clamp Reference]   0   0   0
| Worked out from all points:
|   slope of the pulldown table from 0 to 0.48 V, typ, clamps not added: 15.6 ohm
|   GND clamp passes 1 mA (typ) near -0.71 V on its own axis
|   POWER clamp passes 1 mA (typ) near -0.71 V on its own axis
|   falling waveform, V_fixture 3.2V, R_fixture 50Ohm: 20-80 % time 169ps typ, 181ps min, 159ps max; typ from 3.2 V to 0.761 V
|   rising waveform, V_fixture 3.2V, R_fixture 50Ohm: 20-80 % time 734ps typ, 749ps min, 724ps max; typ from 0.761 V to 3.2 V
[GND Clamp]
-3.2V     -9.26A     -8.23A     -12A
-1.6V     -2.27A     -2.11A     -2.74A
-1.5V     -1.86A     -1.75A     -2.19A
-1.1V     -409mA     -469mA     -279mA
-900mV    -43.4mA    -85.5mA    -4.58mA
3.5V      258pA      23.4mA     20.4pA
4.1V      49.7mA     1.43A      60.1pA
4.3V      440mA      2.12A      630nA
4.5V      1.12A      2.84A      4.66mA
4.8V      2.31A      3.95A      723mA
5.1V      3.57A      5.08A      2.3A
6.4V      9.26A      10.1A      10A
[POWER Clamp]
-3.2V     9.26A      8.13A      12.5A
-1.7V     2.73A      2.48A      3.45A
-1.5V     1.9A       1.77A      2.3A
-1.1V     440mA      496mA      311mA
-900mV    49.7mA     97.1mA     4.69mA
3.5V      -117uA     -20.9mA    -114uA
4.1V      -43.5mA    -1.4A      -134uA
4.3V      -410mA     -2.11A     -141uA
4.5V      -1.08A     -2.84A     -4.73mA
4.8V      -2.27A     -3.97A     -670mA
5.1V      -3.54A     -5.12A     -2.19A
6.4V      -9.26A     -10.2A     -9.67A
[Pulldown]
| Voltage   I(typ)   I(min)  I(max)
-3.2V     -208mA     -200mA     -226mA
-3V       -194mA     -187mA     -202mA
-2.8V     -181mA     -174mA     -188mA
1.1V      70mA       65.9mA     72.8mA
2.3V      142mA      130mA      152mA
3.3V      197mA      170mA      216mA
3.5V      207mA      182mA      229mA
4V        240mA      228mA      260mA
4.3V      271mA      258mA      283mA
4.7V      314mA      299mA      324mA
5.5V      399mA      382mA      433mA
6.4V      494mA      472mA      534mA
[Falling Waveform]
V_fixture = 3.2V
V_fixture_min = 2.7V
V_fixture_max = 3.6V
R_fixture = 50Ohm
C_fixture = 0F
|   Time   V(typ)   V(min)   V(max)
0s        3.2V       2.7V       3.6V
60ps      3.187V     2.7V       3.574V
80ps      3.05V      2.612V     3.376V
120ps     2.395V     2.126V     2.537V
140ps     2.108V     1.877V     2.237V
200ps     1.611V     1.441V     1.705V
300ps     1.152V     1.04V      1.218V
400ps     935.3mV    840.2mV    998mV
700ps     775.4mV    680.2mV    847.4mV
1.98ns    760.8mV    662.6mV    834.9mV
[Rising Waveform]
V_fixture = 3.2V
V_fixture_min = 2.7V
V_fixture_max = 3.6V
R_fixture = 50Ohm
C_fixture = 0F
|   Time   V(typ)   V(min)   V(max)
0s        760.8mV    662.6mV    834.9mV
80ps      781.7mV    690.7mV    847.8mV
200ps     1.304V     1.12V      1.449V
280ps     1.583V     1.347V     1.77V
520ps     2.182V     1.839V     2.456V
800ps     2.592V     2.182V     2.923V
1.12ns    2.855V     2.404V     3.217V
1.48ns    3.013V     2.538V     3.393V
2ns       3.121V     2.631V     3.513V
3.96ns    3.196V     2.697V     3.596V
[Ramp]
|   typ   min   max
dV/dt_r   1.95/4.35E-10   1.63/4.45E-10   2.22/4.28E-10
dV/dt_f   1.96/1.76E-10   1.64/1.88E-10   2.22/1.67E-10
R_load =   50
